VERSION 5.7 ;
  NOWIREEXTENSIONATPIN ON ;
  DIVIDERCHAR "/" ;
  BUSBITCHARS "[]" ;
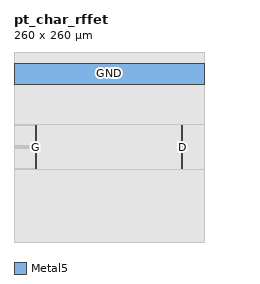
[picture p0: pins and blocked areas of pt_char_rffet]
MACRO pt_char_rffet
  CLASS BLOCK ;
  FOREIGN pt_char_rffet ;
  ORIGIN 130.000 130.000 ;
  SIZE 260.000 BY 260.000 ;
  PIN G
    ANTENNAGATEAREA 2.800000 ;
    PORT
      LAYER Metal5 ;
        RECT -100.260 -30.000 -99.740 30.000 ;
    END
  END G
  PIN D
    ANTENNADIFFAREA 4.860000 ;
    PORT
      LAYER Metal5 ;
        RECT 99.740 -30.000 100.260 30.000 ;
    END
  END D
  PIN GND
    ANTENNADIFFAREA 13.370399 ;
    PORT
      LAYER Metal5 ;
        RECT -130.000 86.000 130.000 114.000 ;
    END
  END GND
  OBS
      LAYER Nwell ;
        RECT -3.940 -2.570 3.940 2.570 ;
      LAYER Metal1 ;
        RECT -3.755 -2.685 3.755 2.385 ;
      LAYER Metal2 ;
        RECT -10.000 -6.300 3.150 2.000 ;
      LAYER Metal3 ;
        RECT -10.000 -100.000 10.000 7.000 ;
      LAYER Metal4 ;
        RECT -120.000 -100.000 120.000 2.000 ;
      LAYER Metal5 ;
        RECT -130.000 114.600 130.000 130.000 ;
        RECT -130.000 114.000 -70.000 114.600 ;
        RECT -130.000 85.400 -70.000 86.000 ;
        RECT -130.000 30.600 130.000 85.400 ;
        RECT -130.000 30.000 -100.860 30.600 ;
        RECT -130.000 1.740 -100.260 30.000 ;
        RECT -130.000 1.460 -100.860 1.740 ;
        RECT -130.000 0.940 -100.260 1.460 ;
        RECT -130.000 0.660 -100.860 0.940 ;
        RECT -130.000 0.140 -100.260 0.660 ;
        RECT -130.000 -0.140 -100.860 0.140 ;
        RECT -130.000 -0.660 -100.260 -0.140 ;
        RECT -130.000 -0.940 -100.860 -0.660 ;
        RECT -130.000 -1.460 -100.260 -0.940 ;
        RECT -130.000 -1.740 -100.860 -1.460 ;
        RECT -130.000 -30.000 -100.260 -1.740 ;
        RECT -130.000 -30.600 -100.860 -30.000 ;
        RECT -99.140 -30.600 99.140 30.600 ;
        RECT 100.860 -30.600 130.000 30.600 ;
        RECT -130.000 -130.000 130.000 -30.600 ;
  END
END pt_char_rffet
END LIBRARY

